VERSION 5.8 ;
BUSBITCHARS "[]" ;
DIVIDERCHAR "/" ;

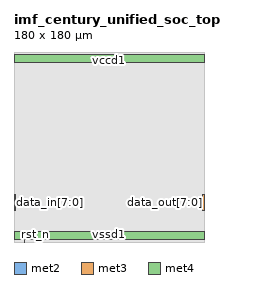
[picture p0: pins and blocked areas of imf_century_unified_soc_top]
MACRO imf_century_unified_soc_top
  CLASS BLOCK ;
  ORIGIN 0.000 0.000 ;
  FOREIGN imf_century_unified_soc_top 0.000 0.000 ;
  SIZE 180.000 BY 180.000 ;
  SYMMETRY X Y R90 ;

  PIN clk
    DIRECTION INPUT ;
    USE SIGNAL ;
    PORT
      LAYER met2 ;
      RECT 10.000 0.000 10.400 1.200 ;
    END
  END clk

  PIN rst_n
    DIRECTION INPUT ;
    USE SIGNAL ;
    PORT
      LAYER met2 ;
      RECT 20.000 0.000 20.400 1.200 ;
    END
  END rst_n

  PIN data_in[7:0]
    DIRECTION INPUT ;
    USE SIGNAL ;
    PORT
      LAYER met3 ;
      RECT 0.000 30.000 1.200 45.000 ;
    END
  END data_in[7:0]

  PIN data_out[7:0]
    DIRECTION OUTPUT ;
    USE SIGNAL ;
    PORT
      LAYER met3 ;
      RECT 178.800 30.000 180.000 45.000 ;
    END
  END data_out[7:0]

  PIN vccd1
    DIRECTION INOUT ;
    USE POWER ;
    PORT
      LAYER met4 ;
      RECT 0.000 170.000 180.000 178.000 ;
    END
  END vccd1

  PIN vssd1
    DIRECTION INOUT ;
    USE GROUND ;
    PORT
      LAYER met4 ;
      RECT 0.000 2.000 180.000 10.000 ;
    END
  END vssd1

  OBS
    LAYER met1 ;
    RECT 0.000 0.000 180.000 180.000 ;
    LAYER met2 ;
    RECT 0.000 0.000 180.000 180.000 ;
  END
END imf_century_unified_soc_top
END LIBRARY
